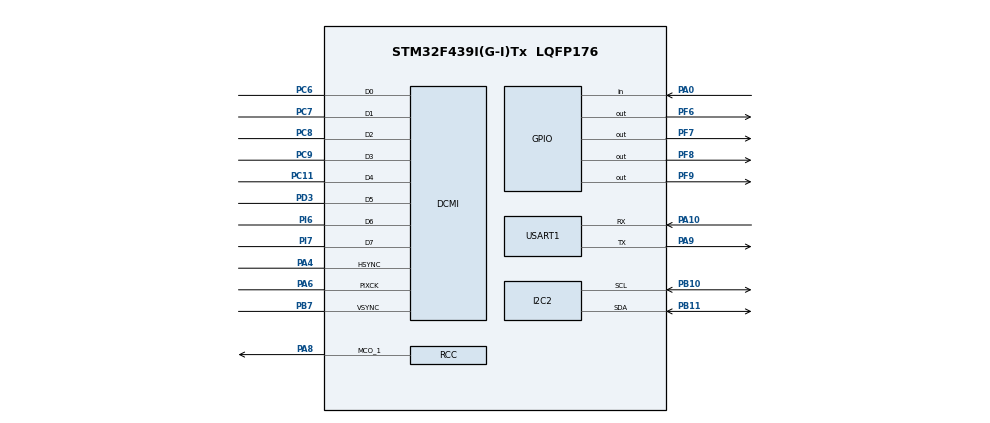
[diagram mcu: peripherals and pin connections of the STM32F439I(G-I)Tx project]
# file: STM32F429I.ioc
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DCMI.JPEGMode=DCMI_JPEG_ENABLE
DCMI.PCKPolarity=DCMI_PCKPOLARITY_RISING
Dma.DCMI.1.Channel=DMA_CHANNEL_1
Dma.DCMI.1.Direction=DMA_PERIPH_TO_MEMORY
Dma.DCMI.1.FIFOMode=DMA_FIFOMODE_ENABLE
Dma.DCMI.1.FIFOThreshold=DMA_FIFO_THRESHOLD_FULL
Dma.DCMI.1.Instance=DMA2_Stream1
Dma.DCMI.1.MemBurst=DMA_MBURST_SINGLE
Dma.DCMI.1.MemDataAlignment=DMA_MDATAALIGN_WORD
Dma.DCMI.1.MemInc=DMA_MINC_ENABLE
Dma.DCMI.1.Mode=DMA_NORMAL
Dma.DCMI.1.PeriphBurst=DMA_PBURST_SINGLE
Dma.DCMI.1.PeriphDataAlignment=DMA_PDATAALIGN_WORD
Dma.DCMI.1.PeriphInc=DMA_PINC_DISABLE
Dma.DCMI.1.Priority=DMA_PRIORITY_VERY_HIGH
Dma.Request0=USART1_TX
Dma.Request1=DCMI
Dma.USART1_TX.0.Channel=DMA_CHANNEL_4
Dma.USART1_TX.0.Direction=DMA_MEMORY_TO_PERIPH
Dma.USART1_TX.0.FIFOMode=DMA_FIFOMODE_ENABLE
Dma.USART1_TX.0.FIFOThreshold=DMA_FIFO_THRESHOLD_FULL
Dma.USART1_TX.0.Instance=DMA2_Stream7
Dma.USART1_TX.0.MemBurst=DMA_MBURST_SINGLE
Dma.USART1_TX.0.MemDataAlignment=DMA_MDATAALIGN_BYTE
Dma.USART1_TX.0.MemInc=DMA_MINC_ENABLE
Dma.USART1_TX.0.Mode=DMA_NORMAL
Dma.USART1_TX.0.PeriphBurst=DMA_PBURST_SINGLE
Dma.USART1_TX.0.PeriphDataAlignment=DMA_PDATAALIGN_BYTE
Dma.USART1_TX.0.PeriphInc=DMA_PINC_DISABLE
Dma.USART1_TX.0.Priority=DMA_PRIORITY_HIGH
I2C2.I2C_Mode=I2C_Standard
Mcu.Family=STM32F4
Mcu.Name=STM32F439I(G-I)Tx
Mcu.Package=LQFP176
NVIC.DCMI_IRQn=true\:0\:0\:false
NVIC.DMA2_Stream1_IRQn=true\:0\:0\:false
NVIC.DMA2_Stream7_IRQn=true\:0\:0\:false
NVIC.PriorityGroup=NVIC_PRIORITYGROUP_4
PA0/WKUP.GPIO_Mode=GPIO_MODE_INPUT
PA0/WKUP.GPIO_PuPd=GPIO_PULLUP
PA0/WKUP.Signal=GPIO_Input
PA10.Mode=Asynchronous
PA10.Signal=USART1_RX
PA4.Mode=Slave_8_bits_External_Synchro
PA4.Signal=DCMI_HSYNC
PA6.Mode=Slave_8_bits_External_Synchro
PA6.Signal=DCMI_PIXCK
PA8.Mode=Clock-out-1
PA8.Signal=RCC_MCO_1
PA9.Mode=Asynchronous
PA9.Signal=USART1_TX
PB10.Mode=I2C
PB10.Signal=I2C2_SCL
PB11.Mode=I2C
PB11.Signal=I2C2_SDA
PB7.Mode=Slave_8_bits_External_Synchro
PB7.Signal=DCMI_VSYNC
PC11.Mode=Slave_8_bits_External_Synchro
PC11.Signal=DCMI_D4
PC6.Mode=Slave_8_bits_External_Synchro
PC6.Signal=DCMI_D0
PC7.Mode=Slave_8_bits_External_Synchro
PC7.Signal=DCMI_D1
PC8.Mode=Slave_8_bits_External_Synchro
PC8.Signal=DCMI_D2
PC9.Mode=Slave_8_bits_External_Synchro
PC9.Signal=DCMI_D3
PD3.Mode=Slave_8_bits_External_Synchro
PD3.Signal=DCMI_D5
PF6.Signal=GPIO_Output
PF7.Signal=GPIO_Output
PF8.Signal=GPIO_Output
PF9.Signal=GPIO_Output
PH0/OSC_IN.Mode=HSE-External-Oscillator
PH0/OSC_IN.Signal=RCC_OSC_IN
PH1/OSC_OUT.Mode=HSE-External-Oscillator
PH1/OSC_OUT.Signal=RCC_OSC_OUT
PI6.Mode=Slave_8_bits_External_Synchro
PI6.Signal=DCMI_D6
PI7.Mode=Slave_8_bits_External_Synchro
PI7.Signal=DCMI_D7
ProjectManager.TargetToolchain=MDK-ARM V5
RCC.48MHZClocksFreq_Value=90000000
RCC.AHBFreq_Value=180000000
RCC.APB1CLKDivider=RCC_HCLK_DIV4
RCC.APB1Freq_Value=45000000
RCC.APB1TimFreq_Value=90000000
RCC.APB2CLKDivider=RCC_HCLK_DIV2
RCC.APB2Freq_Value=90000000
RCC.APB2TimFreq_Value=180000000
RCC.CortexFreq_Value=180000000
RCC.HCLKFreq_Value=180000000
RCC.HSE_VALUE=8000000
RCC.HSI_VALUE=16000000
RCC.LSE_VALUE=32768
RCC.PLLM=8
RCC.PLLN=360
RCC.PLLSourceVirtual=RCC_PLLSOURCE_HSE
RCC.SYSCLKFreq_VALUE=180000000
RCC.SYSCLKSource=RCC_SYSCLKSOURCE_PLLCLK
RCC.VCOOutputFreq_Value=360000000
board=STM32F429I

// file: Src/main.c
/**
  ******************************************************************************
  * File Name          : main.c
  * Description        : Main program body
  ******************************************************************************
  *
  * COPYRIGHT(c) 2015 STMicroelectronics
  *
  * Redistribution and use in source and binary forms, with or without modification,
  * are permitted provided that the following conditions are met:
  *   1. Redistributions of source code must retain the above copyright notice,
  *      this list of conditions and the following disclaimer.
  *   2. Redistributions in binary form must reproduce the above copyright notice,
  *      this list of conditions and the following disclaimer in the documentation
  *      and/or other materials provided with the distribution.
  *   3. Neither the name of STMicroelectronics nor the names of its contributors
  *      may be used to endorse or promote products derived from this software
  *      without specific prior written permission.
  *
  * THIS SOFTWARE IS PROVIDED BY THE COPYRIGHT HOLDERS AND CONTRIBUTORS "AS IS"
  * AND ANY EXPRESS OR IMPLIED WARRANTIES, INCLUDING, BUT NOT LIMITED TO, THE
  * IMPLIED WARRANTIES OF MERCHANTABILITY AND FITNESS FOR A PARTICULAR PURPOSE ARE
  * DISCLAIMED. IN NO EVENT SHALL THE COPYRIGHT HOLDER OR CONTRIBUTORS BE LIABLE
  * FOR ANY DIRECT, INDIRECT, INCIDENTAL, SPECIAL, EXEMPLARY, OR CONSEQUENTIAL
  * DAMAGES (INCLUDING, BUT NOT LIMITED TO, PROCUREMENT OF SUBSTITUTE GOODS OR
  * SERVICES; LOSS OF USE, DATA, OR PROFITS; OR BUSINESS INTERRUPTION) HOWEVER
  * CAUSED AND ON ANY THEORY OF LIABILITY, WHETHER IN CONTRACT, STRICT LIABILITY,
  * OR TORT (INCLUDING NEGLIGENCE OR OTHERWISE) ARISING IN ANY WAY OUT OF THE USE
  * OF THIS SOFTWARE, EVEN IF ADVISED OF THE POSSIBILITY OF SUCH DAMAGE.
  *
  ******************************************************************************
  */
#include "stm32f4xx_hal.h"

/* USER CODE BEGIN Includes */

#include "../BSP/ov2640.h"

/* USER CODE END Includes */

DCMI_HandleTypeDef hdcmi;
DMA_HandleTypeDef hdma_dcmi;

I2C_HandleTypeDef hi2c2;

UART_HandleTypeDef huart1;
DMA_HandleTypeDef hdma_usart1_tx;

/* USER CODE BEGIN PV */
/* Private variables ---------------------------------------------------------*/
uint8_t CAMERA_FRAME_BUFFER [1600*33];
#define BufferLen (sizeof(CAMERA_FRAME_BUFFER)/sizeof(char))
int flag = 0;

/* USER CODE END PV */

void SystemClock_Config(void);
static void MX_GPIO_Init(void);
static void MX_DMA_Init(void);
static void MX_DCMI_Init(void);
static void MX_I2C2_Init(void);
static void MX_USART1_UART_Init(void);

/* USER CODE BEGIN PFP */
/* Private function prototypes -----------------------------------------------*/

/* USER CODE END PFP */

/* USER CODE BEGIN 0 */
/**
  * @brief  Retargets the C library printf function to the USART.
  * @param  None
  * @retval None
  */
int fputc(int ch, FILE *f)
{
  /* write a character to the uart1 and Loop until the end of transmission */
  HAL_UART_Transmit(&huart1, (uint8_t *)&ch, 1, 0xFFFF);

  return ch;
}

/* USER CODE END 0 */

int main(void)
{

  /* MCU Configuration----------------------------------------------------------*/

  /* Reset of all peripherals, Initializes the Flash interface and the Systick. */
  HAL_Init();

  /* Configure the system clock */
  SystemClock_Config();

  /* Initialize all configured peripherals */
  MX_GPIO_Init();
  MX_DMA_Init();
  MX_DCMI_Init();
  MX_I2C2_Init();
  MX_USART1_UART_Init();

  /* USER CODE BEGIN 2 */
	OV2640_JPEGConfig(JPEG_320x240);
	OV2640_BrightnessConfig(0x20);
	OV2640_AutoExposure(2);

  /* USER CODE END 2 */

  /* Infinite loop */
  while (1)
  {

  /* USER CODE BEGIN 3 */
		if(HAL_GPIO_ReadPin(GPIOA,GPIO_PIN_0) == RESET)
		{
			HAL_Delay(10);
			if(HAL_GPIO_ReadPin(GPIOA,GPIO_PIN_0) == RESET)
			{
				HAL_DCMI_Stop(&hdcmi);
				HAL_UART_DMAStop(&huart1);
				MX_DCMI_Init();
				HAL_DCMI_Start_DMA(&hdcmi,DCMI_MODE_SNAPSHOT ,(uint32_t)&CAMERA_FRAME_BUFFER,1600*8);
			}
			while(HAL_GPIO_ReadPin(GPIOA,GPIO_PIN_0) == RESET);
		}
  }
  /* USER CODE END 3 */

}

/** System Clock Configuration
*/
void SystemClock_Config(void)
{

  RCC_OscInitTypeDef RCC_OscInitStruct;
  RCC_ClkInitTypeDef RCC_ClkInitStruct;

  __PWR_CLK_ENABLE();

  __HAL_PWR_VOLTAGESCALING_CONFIG(PWR_REGULATOR_VOLTAGE_SCALE1);

  RCC_OscInitStruct.OscillatorType = RCC_OSCILLATORTYPE_HSI|RCC_OSCILLATORTYPE_HSE;
  RCC_OscInitStruct.HSEState = RCC_HSE_ON;
  RCC_OscInitStruct.HSIState = RCC_HSI_ON;
  RCC_OscInitStruct.HSICalibrationValue = 16;
  RCC_OscInitStruct.PLL.PLLState = RCC_PLL_ON;
  RCC_OscInitStruct.PLL.PLLSource = RCC_PLLSOURCE_HSE;
  RCC_OscInitStruct.PLL.PLLM = 5;
  RCC_OscInitStruct.PLL.PLLN = 210;
  RCC_OscInitStruct.PLL.PLLP = RCC_PLLP_DIV2;
  RCC_OscInitStruct.PLL.PLLQ = 4;
  HAL_RCC_OscConfig(&RCC_OscInitStruct);

  RCC_ClkInitStruct.ClockType = RCC_CLOCKTYPE_SYSCLK|RCC_CLOCKTYPE_PCLK1
                              |RCC_CLOCKTYPE_PCLK2;
  RCC_ClkInitStruct.SYSCLKSource = RCC_SYSCLKSOURCE_PLLCLK;
  RCC_ClkInitStruct.AHBCLKDivider = RCC_SYSCLK_DIV1;
  RCC_ClkInitStruct.APB1CLKDivider = RCC_HCLK_DIV4;
  RCC_ClkInitStruct.APB2CLKDivider = RCC_HCLK_DIV2;
  HAL_RCC_ClockConfig(&RCC_ClkInitStruct, FLASH_LATENCY_5);

  HAL_RCC_MCOConfig(RCC_MCO1, RCC_MCO1SOURCE_HSI, RCC_MCODIV_1);

  HAL_SYSTICK_Config(HAL_RCC_GetHCLKFreq()/1000);

  HAL_SYSTICK_CLKSourceConfig(SYSTICK_CLKSOURCE_HCLK);

}

/* DCMI init function */
void MX_DCMI_Init(void)
{

  hdcmi.Instance = DCMI;
  hdcmi.Init.SynchroMode = DCMI_SYNCHRO_HARDWARE;
  hdcmi.Init.PCKPolarity = DCMI_PCKPOLARITY_RISING;
  hdcmi.Init.VSPolarity = DCMI_VSPOLARITY_LOW;
  hdcmi.Init.HSPolarity = DCMI_HSPOLARITY_LOW;
  hdcmi.Init.CaptureRate = DCMI_CR_ALL_FRAME;
  hdcmi.Init.ExtendedDataMode = DCMI_EXTEND_DATA_8B;
  hdcmi.Init.JPEGMode = DCMI_JPEG_ENABLE;
  HAL_DCMI_Init(&hdcmi);

}

/* I2C2 init function */
void MX_I2C2_Init(void)
{

  hi2c2.Instance = I2C2;
  hi2c2.Init.ClockSpeed = 100000;
  hi2c2.Init.DutyCycle = I2C_DUTYCYCLE_2;
  hi2c2.Init.OwnAddress1 = 0;
  hi2c2.Init.AddressingMode = I2C_ADDRESSINGMODE_7BIT;
  hi2c2.Init.DualAddressMode = I2C_DUALADDRESS_DISABLED;
  hi2c2.Init.OwnAddress2 = 0;
  hi2c2.Init.GeneralCallMode = I2C_GENERALCALL_DISABLED;
  hi2c2.Init.NoStretchMode = I2C_NOSTRETCH_DISABLED;
  HAL_I2C_Init(&hi2c2);

}

/* USART1 init function */
void MX_USART1_UART_Init(void)
{

  huart1.Instance = USART1;
  huart1.Init.BaudRate = 115200;
  huart1.Init.WordLength = UART_WORDLENGTH_8B;
  huart1.Init.StopBits = UART_STOPBITS_1;
  huart1.Init.Parity = UART_PARITY_NONE;
  huart1.Init.Mode = UART_MODE_TX_RX;
  huart1.Init.HwFlowCtl = UART_HWCONTROL_NONE;
  huart1.Init.OverSampling = UART_OVERSAMPLING_16;
  HAL_UART_Init(&huart1);

}

void MX_DMA_Init(void)
{
  /* DMA controller clock enable */
  __DMA2_CLK_ENABLE();

  /* DMA interrupt init */
  HAL_NVIC_SetPriority(DMA2_Stream1_IRQn, 0, 0);
  HAL_NVIC_EnableIRQ(DMA2_Stream1_IRQn);
  HAL_NVIC_SetPriority(DMA2_Stream7_IRQn, 0, 0);
  HAL_NVIC_EnableIRQ(DMA2_Stream7_IRQn);

}

/** Configure pins as
        * Analog
        * Input
        * Output
        * EVENT_OUT
        * EXTI
     PA8   ------> RCC_MCO_1
*/
void MX_GPIO_Init(void)
{

  GPIO_InitTypeDef GPIO_InitStruct;

  /* GPIO Ports Clock Enable */
  __GPIOF_CLK_ENABLE();
  __GPIOH_CLK_ENABLE();
  __GPIOA_CLK_ENABLE();
  __GPIOB_CLK_ENABLE();
  __GPIOC_CLK_ENABLE();
  __GPIOD_CLK_ENABLE();
  __GPIOI_CLK_ENABLE();

  /*Configure GPIO pins : PF6 PF7 PF8 PF9 */
  GPIO_InitStruct.Pin = GPIO_PIN_6|GPIO_PIN_7|GPIO_PIN_8|GPIO_PIN_9;
  GPIO_InitStruct.Mode = GPIO_MODE_OUTPUT_PP;
  GPIO_InitStruct.Pull = GPIO_NOPULL;
  GPIO_InitStruct.Speed = GPIO_SPEED_LOW;
  HAL_GPIO_Init(GPIOF, &GPIO_InitStruct);

  /*Configure GPIO pin : PA0 */
  GPIO_InitStruct.Pin = GPIO_PIN_0;
  GPIO_InitStruct.Mode = GPIO_MODE_INPUT;
  GPIO_InitStruct.Pull = GPIO_PULLUP;
  HAL_GPIO_Init(GPIOA, &GPIO_InitStruct);

  /*Configure GPIO pin : PA8 */
  GPIO_InitStruct.Pin = GPIO_PIN_8;
  GPIO_InitStruct.Mode = GPIO_MODE_AF_PP;
  GPIO_InitStruct.Pull = GPIO_NOPULL;
  GPIO_InitStruct.Speed = GPIO_SPEED_LOW;
  GPIO_InitStruct.Alternate = GPIO_AF0_MCO;
  HAL_GPIO_Init(GPIOA, &GPIO_InitStruct);

}

/* USER CODE BEGIN 4 */

/**
  * @brief  Frame Event callback.
  * @param  hdcmi: pointer to a DCMI_HandleTypeDef structure that contains
  *                the configuration information for DCMI.
  * @retval None
  */
void HAL_DCMI_FrameEventCallback(DCMI_HandleTypeDef *hdcmi)
{
  /* NOTE : This function Should not be modified, when the callback is needed,
            the HAL_DCMI_FrameEventCallback could be implemented in the user file
   */
	HAL_UART_Transmit_DMA(&huart1, (uint8_t*)CAMERA_FRAME_BUFFER, BufferLen);
}

/* USER CODE END 4 */

/************************ (C) COPYRIGHT STMicroelectronics *****END OF FILE****/
